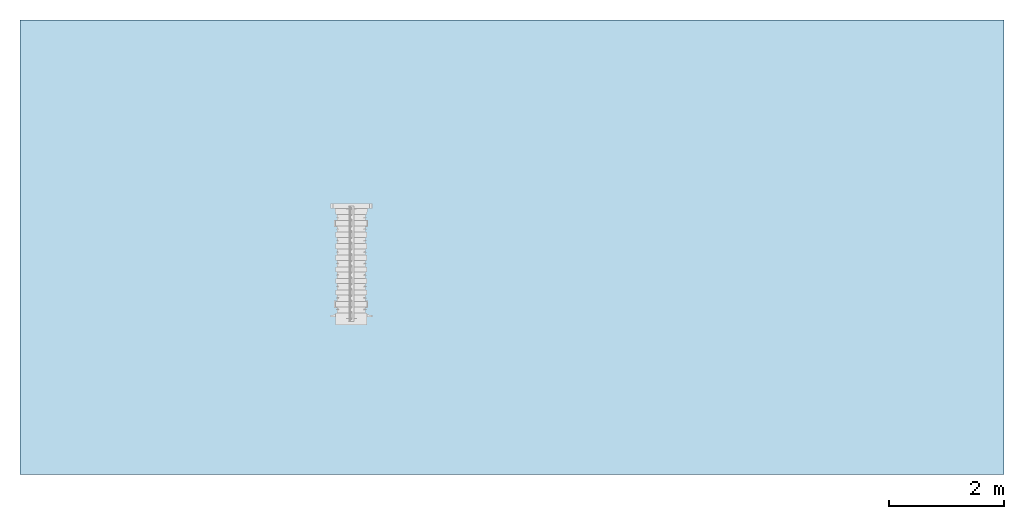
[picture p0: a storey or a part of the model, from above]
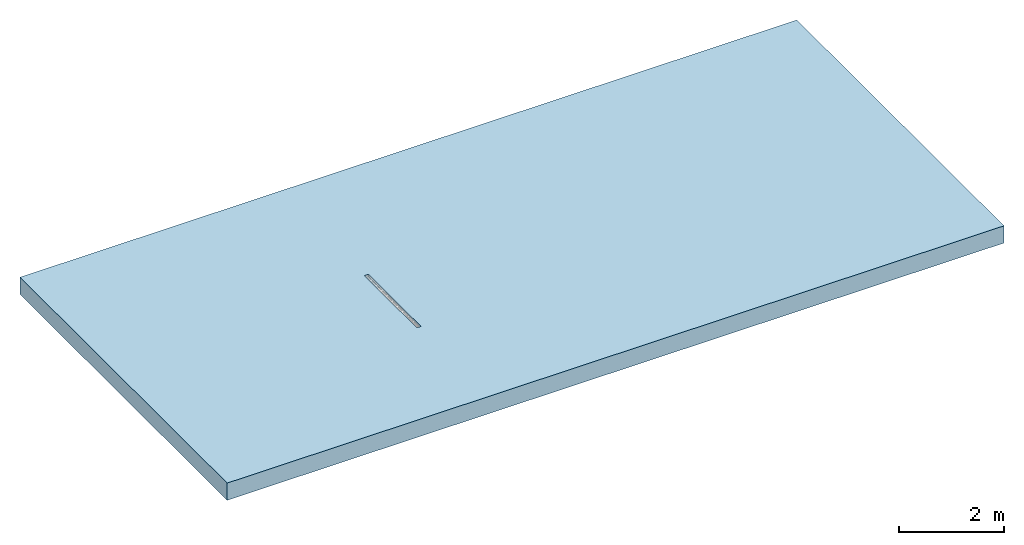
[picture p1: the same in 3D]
Properties of the parts of a building model (IFC2X3)

# File
Description: ViewDefinition [CoordinationView]
File name: 32832 - Q-Flow Edge - G.S.ifc
Time: 2013-07-11T16:55:54
Written by: Autodesk Revit 2013
Made in: 20120221_2030(x64)

# IfcProject, Project Number
LongName: Project Name; Phase: Project Status

# IfcSite, Default
RefLatitude: 42, 21, 30, 344238; RefLongitude: -71, -3, -35, -194702; RefElevation: 0 mm

# IfcBuilding
Pset_BuildingCommon - NumberOfStoreys: 1
Other - Project Status: Project Status; Project Number: Project Number; Client Name: Owner; Project Address: ## Street City, State Zip; Project Issue Date: Issue Date; Project Name: Project Name

# IfcBuildingStorey, Level 1
LongName: Level 1; Elevation: 0 mm
Constraints - Elevation Base: 0; Elevation: 0 mm
Graphics - Color: 0; Symbol at End 2 Default: yes; Symbol: M_Level Head - Circle: M_Level Head - Circle; Line Pattern: Center; Symbol at End 1 Default: no; Line Weight: 1
Identity Data - Building Story: yes; Structural: no; Name: Level 1
Dimensions - Computation Height: 0 mm

# IfcFlowTerminal: 32832 - Q-Flow Edge - G.S, Qmax 700:32832 - Q-Flow Edge - G.S:32832 - Q-Flow Edge - G.S:502881
In: Level 1
Construction - 32835_Closing End cap (at Female end): no; 32835_Closing End cap (at Male end): yes; 32854_Chamber connector (at Female end): no; 32854_Chamber connector (at Male end): no; 32882_550-700 Step Connector: no; E5-QSlot-GalvSteel: no; V_Coarse_E5: no; V_CoarseE1: yes; E1-QFlow-DuctileIron: no; E3-QFlow-GalvSteel: yes; E4-QGuard-GalvSteel: no; E2-QGuard-DuctileIron: no
Constraints - Moves With Nearby Elements: no; Level: Level: Level 1
Identity Data - Mark: 37; OmniClass Title: Rainwater Removal; Assembly Code: D2040; OmniClass Number: 23.70.50.24; Manufacturer: ACO Technologies plc - ACO Water Management Division; Fax: +44 (0)1462 815895; Assembly Description: Rain Water Drainage; Product Code: 32832; e-mail Sales: customersupport@aco.co.uk; Product Brochure: http://www.aco.co.uk/download.php?id=220; URL: www.aco.co.uk; Price: POA - contact ACO; Address: ACO Business Park, Hitchin Road, Shefford, Bedfordshire, United Kingdom SG17 5TE; Type Comments: ACO Qmax 700 channel assembly complete with ACO Q-Flow galvanised steel edge rail; Installation Guidelines: http://www.aco.co.uk/download.php?id=220; Cost: 0; Product Page URL: http://www.aco.co.uk/product_detail.php?id=79; e-mail Technical: technical@aco.co.uk; Model Description: High capacity slot drainage channel system; Model: ACO Qmax 700; Telephone: +44 (0)1462 816666; Maintenance Guidelines: http://www.aco.co.uk/download.php?id=220
Phasing - Phase Created: New Construction
Model Properties - Chamber Connector Product Code: 32854; 550-700 Step Connector Weight: 2.5 kg; Closing End Cap Colour: Black; Chamber Connector Recyclable: Fully recyclable; Closing End Cap Product Code: 32835; 550-700 Step Connector Product Code: 32882; 550-700 Step Connector Colour: Black; Closing End Cap Recyclable: Fully recyclable; Closing End Cap Model Description: High capacity slot drainage channel system; 550-700 Step Connector Recyclable: Fully recyclable; Chamber Connector Model Description: High capacity slot drainage channel system; 550-700 Step Connector Recycled Material Content: 0%; 550-700 Step Connector Dimensions: 730mm x 45mm x 865mm (LxWxH); Closing End Cap Material: High Density Polyethylene; Chamber Connector Channel Colour: Black; Chamber Connector Weight: 15.8 kg; Chamber Connector Channel Material: Medium Density Polyethylene; Chamber Connector Recycled Material Content: Variable %; Closing End Cap Recycled Material Content: 0%; Closing End Cap Dimensions: 730mm x 12mm x 865mm (LxWxH); 550-700 Step Connector Model Description: High capacity slot drainage channel system; Chamber Connector Dimensions: Female End=800mm x 715mm x 895mm, Male End=800mm x 715mm x 845mm (LxWxH); Closing End Cap Weight: 4.9 kg; 550-700 Step Connector Material: High Density Polyethylene
Dimensions - Floor Opening Width: 90 mm; Length: 2000 mm; ChamberOrigin: 480 mm; StepConn-Origin: 580.3 mm; Width Overall: 730 mm; ClosingEndCapOrigin: 570.2 mm; Depth Overall: 1070 mm
Data - Product Standard: BS EN 1433:2002 CE marked; ACO Hydraulic Design Software: http://www.acodesign.co.uk; Product Weight: 41.9 kg; Drainage Slot Width: 26mm; Load Class: A 15 - F 900; Channel C.S.A: 249703mm²; Invert Depth: 950mm; Installation - Concrete Grade: Refer to brochure; Drainage Slot Intake Area: 18106mm²/m; Installation - Reinforcement Details: Refer to brochure; Product Dimensions: 2000mm x 730mm x 1070mm (LxWxH); Concrete Surround Volume - Load Class E 600 - F 900: 0.72 m³/m; Concrete Surround Volume - Load Class A 15 - D 400: 0.56 m³/m; Hydraulic Performance: http://www.aco.co.uk/download.php?id=220
Green Building Properties - Channel Recycled Material Content: Variable %; Channel Recyclable: Fully recyclable; Seal Recycled Material Content: 0%; Edge Rail Recycled Material Content: Between 40% - 90%; Edge Rail Recyclable: Fully recyclable; Seal Recyclable: Fully recyclable
General - TagNumber: 0; SerialNumber: 0
Other - Created by: www.aco.co.uk; Revision: 1
Materials and Finishes - Channel Colour: Black; Edge Rail Finish: Galvanised; Edge Rail Colour: Silver Silver; Seal Material: EPDM; Seal Colour: Black; Channel Material: Medium Density Polyethylene; Edge Rail Material: Steel

# IfcOpeningElement: Opening
In: Level 1
Dimensions - Volume: 53460000000 mm3; Area: 134910000 mm2; Perimeter: 50000 mm; Thickness: 400 mm
Phasing - Phase Created: New Construction
Constraints - Room Bounding: yes; Related to Mass: no; Level: Level: Level 1; Height Offset From Level: 0 mm
Structural - Enable Analytical Model: no; Structural: no
Analytical Properties - Absorptance: 0.1; Roughness: 1
Graphics - Coarse Scale Fill Color: 0
Construction - Function: 0; Default Thickness: 400 mm
Materials and Finishes - Structural Material: Plant

# IfcSlab: Floor:Generic Floor - 400mm, Floor:Generic Floor - 400mm:193825
In: Level 1
PredefinedType: FLOOR; Material: Plant 400 mm
Dimensions - Volume: 53460000000 mm3; Area: 134910000 mm2; Perimeter: 50000 mm; Thickness: 400 mm
Phasing - Phase Created: New Construction
Constraints - Room Bounding: yes; Related to Mass: no; Level: Level: Level 1; Height Offset From Level: 0 mm
Structural - Enable Analytical Model: no; Structural: no
Pset_SlabCommon - Reference: Generic Floor - 400mm; IsExternal: no; LoadBearing: yes
Analytical Properties - Absorptance: 0.1; Roughness: 1
Graphics - Coarse Scale Fill Color: 0
Construction - Function: 0; Default Thickness: 400 mm
Materials and Finishes - Structural Material: Plant
